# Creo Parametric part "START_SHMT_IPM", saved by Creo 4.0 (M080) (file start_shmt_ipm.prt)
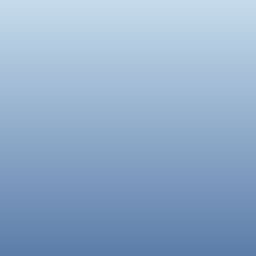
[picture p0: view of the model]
Units: IPM (mmkgsecC); MM, KILOGRAM, SECS
Materials in the file: OCEL, HLINIK, MED, MOSADZ, TEFLON

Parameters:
  PTC_MATERIAL_NAME = "OCEL"
  SMT_PART_BEND_TABLE_NAME = "TABULKA_OHYBOV"
  PRO_UNIT_SYS = "IPM (mmkgsecC)"

Other parameters: HMOTNOST, SMT_THICKNESS, SMT_PART_BEND_ALLOWANCE_FACTOR, SMT_DFLT_BEND_RADIUS, SMT_DFLT_BEND_ANGLE, SMT_DFLT_CRNR_REL_WIDTH, SMT_DFLT_CRNR_REL_DEPTH, SMT_DFLT_BEND_REL_WIDTH, SMT_DFLT_BEND_REL_DEPTH, SMT_DFLT_BEND_REL_ANGLE, SMT_GAP, SMT_DFLT_EDGE_TREA_WIDTH, SMT_DFLT_MITER_CUT_WIDTH, SMT_DFLT_MITER_CUT_OFFSET, HUSTOTA

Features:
  1. datum plane "BOKORYS"
  2. datum plane "PODORYS"
  3. datum plane "NARYS"
  4. coordinate system

Other named items: KSYS

Layers: 01_STD_KSYS, 02_STD_ROVINY, 03_KSYS, 04_ROVINY, 05_OSI, 06_BODY, 07_KRIVKY, 08_PLOCHY, 09_QUILTY, 10_DIERY, 11_ZAVITY, 12_KOZMETICKE_PRVKY, 13_KOPIROVANA_GEOM, 14_EXT_KOPIROVANA_GEOM, 15_SKELETONY, XSEC_ROVINY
